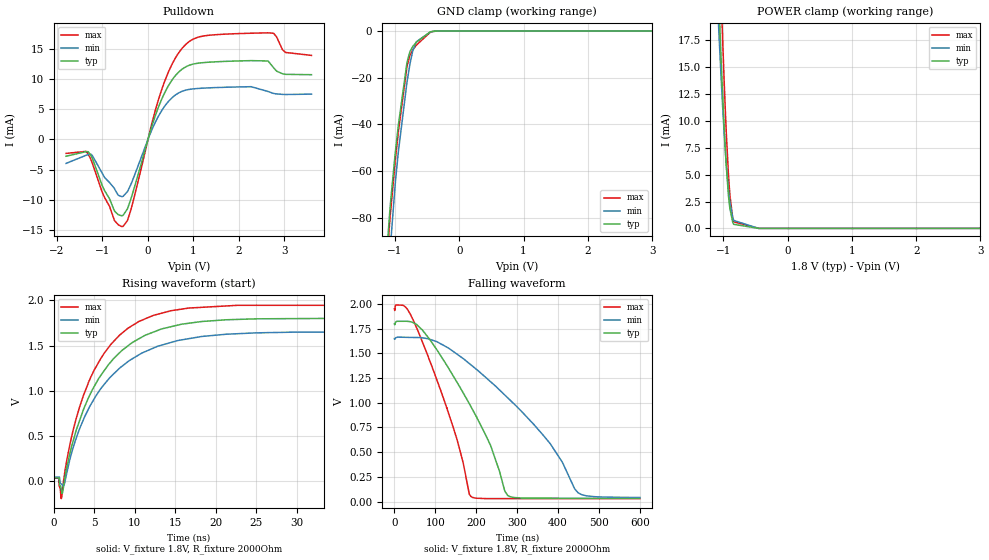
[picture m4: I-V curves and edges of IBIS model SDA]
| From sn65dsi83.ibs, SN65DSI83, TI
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|   Model
[Model]   SDA
Model_type   I/O_open_drain
Polarity   Non-Inverting
Enable   Active-Low
Vinl = 0.54
Vinh = 1.26
Vmeas = 0.9
Vref = 1.8
Cref = 1pF
Rref = 2000
|   typ   min   max
C_comp   0.4063pF   0.3201pF   0.4932pF
[Voltage Range]   1.8   1.65   1.95
[Temperature Range]   27   125   -40
[Pullup Reference]   1.8   1.65   1.95
[Pulldown Reference]   -0   -0   -0
[Power Clamp Reference]   1.8   1.65   1.95
[GND Clamp Reference]   -0   -0   -0
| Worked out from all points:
|   slope of the pulldown table from 0 to 0.27 V, typ, clamps not added: 44.3 ohm
|   GND clamp passes 1 mA (typ) near -0.48 V on its own axis
|   POWER clamp passes 1 mA (typ) near -0.87 V on its own axis
|   falling waveform, V_fixture 1.8V, R_fixture 2000Ohm: 20-80 % time 133ns typ, 211ns min, 93.5ns max; typ from 1.8 V to 0.033 V
|   rising waveform, V_fixture 1.8V, R_fixture 2000Ohm: 20-80 % time 6.22ns typ, 6.88ns min, 5.6ns max; typ from 0.033 V to 1.8 V
[Pulldown]
|   Voltage   I(typ)   I(min)   I(max)
-1.8V     -2.775mA   -3.966mA   -2.31mA
-1.357V   -2.016mA   -2.616mA   -1.971mA
-1.228V   -3.037mA   -2.635mA   -3.85mA
-741.6mV  -11.77mA   -8.078mA   -13.35mA
-547.2mV  -12.58mA   -9.429mA   -14.42mA
-374.4mV  -9.845mA   -7.437mA   -11.63mA
306mV     6.753mA    4.837mA    8.369mA
835.2mV   12.07mA    8.193mA    15.8mA
2.266V    13.08mA    8.754mA    17.62mA
2.758V    11.94mA    7.639mA    17.62mA
3.028V    10.8mA     7.46mA     14.43mA
3.595V    10.74mA    7.52mA     13.95mA
[GND Clamp]
|   Voltage   I(typ)   I(min)   I(max)
-1.8V     -584.9mA   -593.4mA   -587.7mA
-1.114V   -89.8mA    -112.3mA   -93.69mA
-1.082V   -77.55mA   -96.92mA   -81.84mA
-1.071V   -73.87mA   -92.25mA   -78.17mA
-995.4mV  -52.02mA   -65.11mA   -55.54mA
-946.8mV  -40.11mA   -51.48mA   -43.05mA
-806.4mV  -12.73mA   -20.71mA   -14.42mA
-768.6mV  -8.918mA   -14.34mA   -10.5mA
-725.4mV  -6.688mA   -8.715mA   -8.197mA
-666mV    -4.741mA   -4.563mA   -5.991mA
-450mV    -340.3uA   -406.7uA   -515.3uA
3.595V    0A         0A         0A
[POWER Clamp]
|   Voltage   I(typ)   I(min)   I(max)
-1.8V     160.5mA    134.1mA    187.1mA
-1.071V   21.35mA    18.46mA    28.34mA
-1.066V   20.49mA    17.78mA    27.33mA
-1.033V   15.58mA    13.84mA    21.4mA
-1.012V   12.54mA    11.4mA     17.66mA
-963mV    6.674mA    6.674mA    10.11mA
-919.8mV  3.033mA    3.571mA    4.947mA
-898.2mV  1.861mA    2.46mA     3.113mA
-855mV    598.6uA    1.047mA    989.3uA
-838.8mV  377.2uA    737.7uA    607uA
-450mV    369.4pA    86.94nA    24.51nA
3.595V    0A         0A         0A
[Ramp]
R_load = 2000
|   typ   min   max
dV/dt_r   1.06013/6.22272e-09   0.965093/6.88395e-09   1.15222/5.59552e-09
dV/dt_f   1.06013/1.32582e-07   0.964806/2.11092e-07   1.15222/9.34972e-08
[Falling Waveform]
V_fixture = 1.8V
V_fixture_min = 1.65V
V_fixture_max = 1.95V
R_fixture = 2000Ohm
C_fixture = 0F
|   Time   V(typ)   V(min)   V(max)
0s        1.8V       1.65V      1.95V
26.88ns   1.825V     1.662V     1.97V
60.63ns   1.767V     1.66V      1.697V
142.7ns   1.278V     1.522V     764.8mV
186.7ns   963.8mV    1.385V     53.22mV
234.9ns   570.1mV    1.213V     30.47mV
281.5ns   52.05mV    1.032V     30.32mV
381.2ns   34.76mV    584.5mV    30.01mV
449.1ns   33.82mV    89.43mV    29.79mV
600ns     33.11mV    41.95mV    29.63mV
[Rising Waveform]
V_fixture = 1.8V
V_fixture_min = 1.65V
V_fixture_max = 1.95V
R_fixture = 2000Ohm
C_fixture = 0F
|   Time   V(typ)   V(min)   V(max)
0s        33.11mV    41.47mV    29.63mV
622.9ps   33.58mV    41.88mV    30.53mV
915.9ps   -92.68mV   -32.79mV   -196.7mV
1.256ns   -28.93mV   -48.18mV   33.93mV
2.052ns   329.9mV    262.4mV    431.7mV
3.668ns   791.6mV    681.4mV    949.1mV
8.147ns   1.422V     1.251V     1.617V
13.29ns   1.683V     1.504V     1.858V
22.75ns   1.789V     1.631V     1.946V
600ns     1.8V       1.65V      1.95V
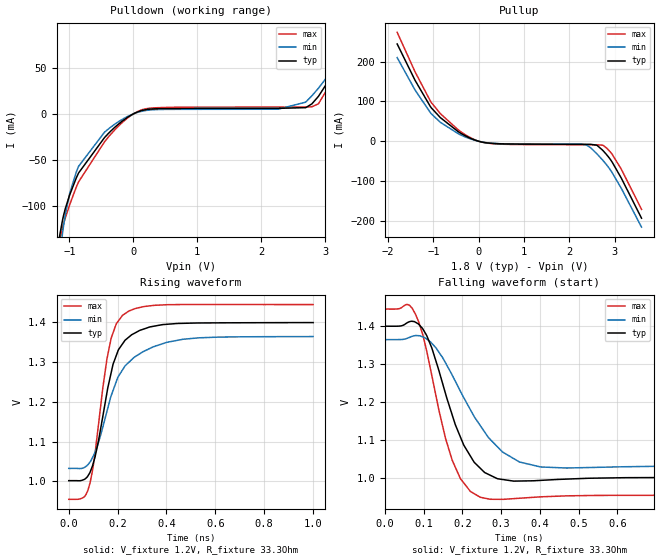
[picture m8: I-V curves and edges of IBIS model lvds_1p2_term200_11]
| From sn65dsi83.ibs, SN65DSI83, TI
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|   Model
[Model]   lvds_1p2_term200_11
Model_type   Output
Polarity   Non-Inverting
Vmeas = 1.2
Vref = 1.2
Cref = 1pF
Rref = 50
|   typ   min   max
C_comp   0.4797pF   0.3035pF   0.7186pF
[Voltage Range]   1.8   1.65   1.95
[Temperature Range]   27   125   -40
[Pullup Reference]   1.8   1.65   1.95
[Pulldown Reference]   -0   -0   -0
[Power Clamp Reference]   1.8   1.65   1.95
[GND Clamp Reference]   -0   -0   -0
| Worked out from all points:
|   slope of the pulldown table from 0 to 0.27 V, typ, clamps not added: 51.5 ohm
|   slope of the pullup table from 0 to 0.27 V, typ, clamps not added: 53.5 ohm
|   falling waveform, V_fixture 1.2V, R_fixture 33.3Ohm: 20-80 % time 78.9ps typ, 115ps min, 67ps max; typ from 1.4 V to 1 V
|   rising waveform, V_fixture 1.2V, R_fixture 33.3Ohm: 20-80 % time 81.9ps typ, 121ps min, 65.7ps max; typ from 1 V to 1.4 V
[Pulldown]
|   Voltage   I(typ)   I(min)   I(max)
-1.8V     -663.5mA   -698.3mA   -654.1mA
-1.152V   -133mA     -155.2mA   -138.3mA
-1.103V   -114.8mA   -128.5mA   -123.5mA
-995.4mV  -88.42mA   -86.86mA   -99.1mA
-855mV    -64.32mA   -57.05mA   -73.99mA
-450mV    -25.77mA   -19.91mA   -30.43mA
-190.8mV  -8.811mA   -6.71mA    -10.55mA
262.8mV   5.207mA    4.291mA    6.243mA
2.261V    6.061mA    5.108mA    7.461mA
2.693V    6.82mA     12.79mA    7.511mA
2.893V    19.13mA    27.99mA    11.02mA
3.595V    94.35mA    91.7mA     92.44mA
[Pullup]
|   Voltage   I(typ)   I(min)   I(max)
-1.8V     244.4mA    210mA      273.6mA
-1.406V   153.1mA    128.7mA    174.4mA
-1.044V   83.58mA    68.78mA    96.92mA
-844.2mV  59.17mA    47.38mA    69.07mA
-374.4mV  18.58mA    14.61mA    22.18mA
230.4mV   -4.647mA   -4.344mA   -5.204mA
2.374V    -7.591mA   -9.141mA   -8.793mA
2.612V    -10.2mA    -31.83mA   -8.858mA
2.747V    -23.83mA   -48.59mA   -10.46mA
2.909V    -46.07mA   -72.36mA   -27.39mA
3.141V    -91.19mA   -116.8mA   -68.85mA
3.595V    -193.3mA   -215.7mA   -171mA
[Ramp]
R_load = 33.3
|   typ   min   max
dV/dt_r   0.238412/8.19288e-11   0.198831/1.21179e-10   0.293736/6.57417e-11
dV/dt_f   0.238598/7.88635e-11   0.198831/1.15347e-10   0.293717/6.69726e-11
[Falling Waveform]
V_fixture = 1.2V
V_fixture_min = 1.2V
V_fixture_max = 1.2V
R_fixture = 33.3Ohm
C_fixture = 0F
|   Time   V(typ)   V(min)   V(max)
0s        1.399V     1.364V     1.444V
58.42ps   1.409V     1.368V     1.456V
78.53ps   1.41V      1.375V     1.431V
121ps     1.342V     1.354V     1.269V
173.4ps   1.166V     1.271V     1.047V
203.3ps   1.087V     1.212V     987.5mV
246.1ps   1.026V     1.138V     949.8mV
303.3ps   996.5mV    1.069V     944.4mV
401.3ps   994.1mV    1.029V     950.8mV
1ns       1.002V     1.033V     954.9mV
[Rising Waveform]
V_fixture = 1.2V
V_fixture_min = 1.2V
V_fixture_max = 1.2V
R_fixture = 33.3Ohm
C_fixture = 0F
|   Time   V(typ)   V(min)   V(max)
0s        1.002V     1.033V     955mV
58.42ps   1.004V     1.034V     959mV
78.53ps   1.014V     1.042V     977.8mV
107.7ps   1.062V     1.074V     1.072V
156.3ps   1.223V     1.176V     1.308V
181.4ps   1.295V     1.229V     1.374V
220.4ps   1.346V     1.281V     1.418V
303.3ps   1.382V     1.326V     1.439V
467.8ps   1.397V     1.357V     1.445V
1ns       1.399V     1.364V     1.445V
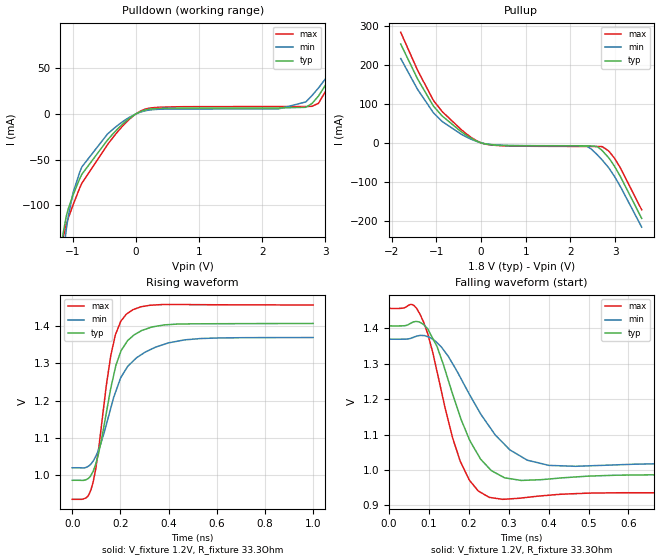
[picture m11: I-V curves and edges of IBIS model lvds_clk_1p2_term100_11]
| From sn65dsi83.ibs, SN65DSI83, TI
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|   Model
[Model]   lvds_clk_1p2_term100_11
Model_type   Output
Polarity   Non-Inverting
Vmeas = 1.2
Vref = 1.2
Cref = 1pF
Rref = 50
|   typ   min   max
C_comp   0.4797pF   0.3035pF   0.7186pF
[Voltage Range]   1.8   1.65   1.95
[Temperature Range]   27   125   -40
[Pullup Reference]   1.8   1.65   1.95
[Pulldown Reference]   -0   -0   -0
[Power Clamp Reference]   1.8   1.65   1.95
[GND Clamp Reference]   -0   -0   -0
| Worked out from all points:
|   slope of the pulldown table from 0 to 0.27 V, typ, clamps not added: 47.8 ohm
|   slope of the pullup table from 0 to 0.27 V, typ, clamps not added: 51 ohm
|   falling waveform, V_fixture 1.2V, R_fixture 33.3Ohm: 20-80 % time 80.4ps typ, 114ps min, 69.2ps max; typ from 1.41 V to 0.986 V
|   rising waveform, V_fixture 1.2V, R_fixture 33.3Ohm: 20-80 % time 83.4ps typ, 121ps min, 68.1ps max; typ from 0.986 V to 1.41 V
[Pulldown]
|   Voltage   I(typ)   I(min)   I(max)
-1.8V     -663.1mA   -698.1mA   -653.7mA
-1.152V   -130.3mA   -153.7mA   -135.1mA
-1.103V   -112.2mA   -126.9mA   -121mA
-995.4mV  -88.66mA   -86.14mA   -99.5mA
-855mV    -65.92mA   -57.84mA   -75.73mA
-450mV    -28.58mA   -21.98mA   -33.64mA
-93.6mV   -4.36mA    -3.331mA   -5.241mA
306mV     5.863mA    4.925mA    7.022mA
2.261V    6.528mA    5.493mA    8.061mA
2.693V    7.281mA    13.15mA    8.114mA
2.893V    19.56mA    28.35mA    11.59mA
3.595V    94.78mA    92.06mA    92.98mA
[Pullup]
|   Voltage   I(typ)   I(min)   I(max)
-1.8V     253.2mA    216mA      283.3mA
-1.417V   162.5mA    135.9mA    184.7mA
-1.06V    93.03mA    76.04mA    107.5mA
-860.4mV  67.75mA    53.72mA    78.86mA
-266.4mV  14.69mA    11.42mA    17.59mA
-1.8mV    65.47uA    55uA       74.58uA
306mV     -5.616mA   -5.305mA   -6.335mA
2.369V    -7.899mA   -9.004mA   -9.275mA
2.596V    -9.628mA   -30.05mA   -9.418mA
2.876V    -41.46mA   -67.29mA   -23.81mA
3.109V    -84.77mA   -110.5mA   -62.76mA
3.595V    -193.9mA   -216.2mA   -171.8mA
[Ramp]
R_load = 33.3
|   typ   min   max
dV/dt_r   0.252559/8.34033e-11   0.209765/1.20974e-10   0.313028/6.80895e-11
dV/dt_f   0.252642/8.04279e-11   0.209765/1.14095e-10   0.312945/6.92397e-11
[Falling Waveform]
V_fixture = 1.2V
V_fixture_min = 1.2V
V_fixture_max = 1.2V
R_fixture = 33.3Ohm
C_fixture = 0F
|   Time   V(typ)   V(min)   V(max)
0s        1.407V     1.369V     1.457V
58.42ps   1.417V     1.373V     1.467V
78.53ps   1.417V     1.38V      1.44V
121ps     1.349V     1.36V      1.278V
178.8ps   1.15V      1.262V     1.025V
201.4ps   1.087V     1.215V     971.6mV
251.7ps   1.004V     1.123V     922.3mV
303ps     975.3mV    1.057V     918.1mV
401ps     974.2mV    1.013V     928.4mV
1ns       986mV      1.02V      935mV
[Rising Waveform]
V_fixture = 1.2V
V_fixture_min = 1.2V
V_fixture_max = 1.2V
R_fixture = 33.3Ohm
C_fixture = 0F
|   Time   V(typ)   V(min)   V(max)
0s        986.2mV    1.02V      935mV
55.03ps   987.2mV    1.02V      938.2mV
78.53ps   1V         1.03V      961.9mV
107.7ps   1.053V     1.065V     1.062V
160.1ps   1.233V     1.18V      1.321V
178.8ps   1.288V     1.221V     1.376V
224ps     1.355V     1.285V     1.432V
331.6ps   1.398V     1.339V     1.456V
467.6ps   1.406V     1.363V     1.458V
1ns       1.407V     1.369V     1.457V
